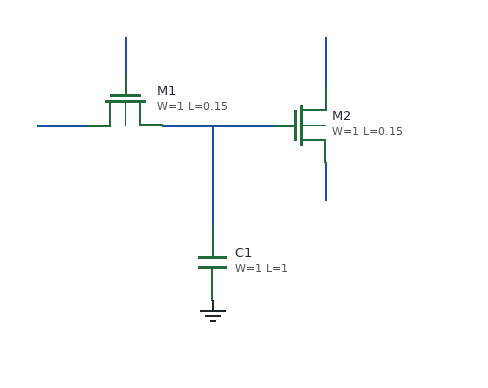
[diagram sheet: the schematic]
v {xschem version=3.4.7 file_version=1.2}
G {}
K {}
V {}
S {}
E {}
N -40 0 50 0 {lab=#net1}
N -70 -70 -70 -40 {lab=#net2}
N -140 0 -100 -0 {lab=#net3}
N 90 -70 90 -30 {lab=#net4}
N 90 30 90 60 {lab=#net5}
N 0 0 0 80 {lab=#net1}
C {sky130_fd_pr/nfet_01v8.sym} -70 -20 1 0 {name=M1
L=0.15
W=1
nf=1 
mult=1
ad="'int((nf+1)/2) * W/nf * 0.29'" 
pd="'2*int((nf+1)/2) * (W/nf + 0.29)'"
as="'int((nf+2)/2) * W/nf * 0.29'" 
ps="'2*int((nf+2)/2) * (W/nf + 0.29)'"
nrd="'0.29 / W'" nrs="'0.29 / W'"
sa=0 sb=0 sd=0
model=nfet_01v8
spiceprefix=X
}
C {sky130_fd_pr/nfet_01v8.sym} 70 0 0 0 {name=M2
L=0.15
W=1
nf=1 
mult=1
ad="'int((nf+1)/2) * W/nf * 0.29'" 
pd="'2*int((nf+1)/2) * (W/nf + 0.29)'"
as="'int((nf+2)/2) * W/nf * 0.29'" 
ps="'2*int((nf+2)/2) * (W/nf + 0.29)'"
nrd="'0.29 / W'" nrs="'0.29 / W'"
sa=0 sb=0 sd=0
model=nfet_01v8
spiceprefix=X
}
C {sky130_fd_pr/cap_mim_m3_1.sym} 0 110 0 0 {name=C1 model=cap_mim_m3_1 W=1 L=1 MF=1 spiceprefix=X}
C {devices/gnd.sym} 0 140 0 0 {name=l1 lab=GND}
